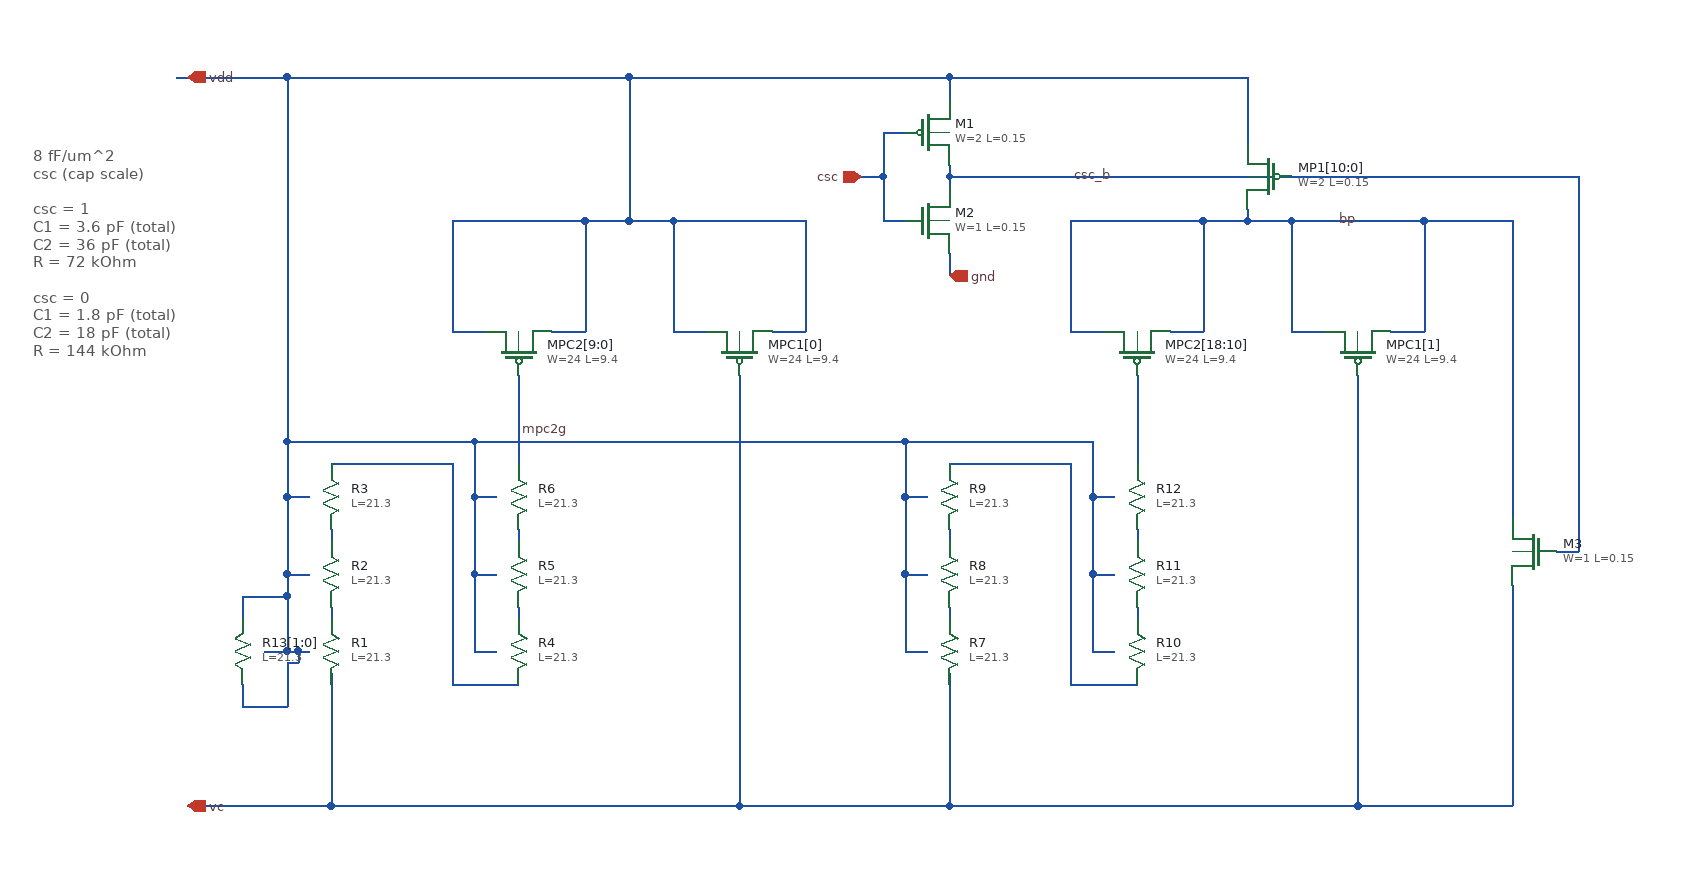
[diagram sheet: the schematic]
v {xschem version=3.4.5 file_version=1.2
}
G {}
K {}
V {}
S {}
E {}
T {8 fF/um^2
csc (cap scale)

csc = 1
C1 = 3.6 pF (total)
C2 = 36 pF (total)
R = 72 kOhm 

csc = 0
C1 = 1.8 pF (total)
C2 = 18 pF (total)
R = 144 kOhm } -50 -720 0 0 0.4 0.4 {}
N 190 -260 200 -260 {
lab=vdd}
N 530 -650 650 -650 {
lab=vdd}
N 330 -550 360 -550 {
lab=vdd}
N 330 -650 330 -550 {
lab=vdd}
N 420 -550 450 -550 {
lab=vdd}
N 450 -650 450 -550 {
lab=vdd}
N 330 -650 450 -650 {
lab=vdd}
N 220 -430 330 -430 {
lab=#net1}
N 390 -510 390 -430 {
lab=mpc2g}
N 530 -550 560 -550 {
lab=vdd}
N 530 -650 530 -550 {
lab=vdd}
N 620 -550 650 -550 {
lab=vdd}
N 650 -650 650 -550 {
lab=vdd}
N 590 -510 590 -120 {
lab=vc}
N 1150 -120 1290 -120 {
lab=vc}
N 490 -650 530 -650 {
lab=vdd}
N 220 -240 220 -120 {
lab=vc}
N 1090 -650 1210 -650 {
lab=csc_b}
N 890 -550 920 -550 {
lab=csc_b}
N 890 -650 890 -550 {
lab=csc_b}
N 980 -550 1010 -550 {
lab=csc_b}
N 1010 -650 1010 -550 {
lab=csc_b}
N 890 -650 1010 -650 {
lab=csc_b}
N 1090 -550 1120 -550 {
lab=csc_b}
N 1090 -650 1090 -550 {
lab=csc_b}
N 1180 -550 1210 -550 {
lab=csc_b}
N 1210 -650 1210 -550 {
lab=csc_b}
N 1150 -510 1150 -120 {
lab=vc}
N 1050 -650 1090 -650 {
lab=csc_b}
N 780 -690 780 -680 {
lab=csc_b}
N 720 -730 740 -730 {
lab=csc}
N 720 -690 720 -650 {
lab=csc}
N 720 -650 740 -650 {
lab=csc}
N 780 -780 780 -760 {
lab=vdd}
N 780 -620 780 -600 {
lab=gnd}
N 1010 -650 1050 -650 {
lab=csc_b}
N 1210 -650 1290 -650 {
lab=csc_b}
N 1290 -650 1290 -380 {
lab=csc_b}
N 1290 -320 1290 -120 {
lab=vc}
N 180 -400 180 -330 {
lab=vdd}
N 780 -780 1050 -780 {
lab=vdd}
N 80 -780 180 -780 {
lab=vdd}
N 1330 -350 1350 -350 {
lab=csc_b}
N 490 -780 780 -780 {
lab=vdd}
N 490 -780 490 -650 {
lab=vdd}
N 180 -780 490 -780 {
lab=vdd}
N 450 -650 490 -650 {
lab=vdd}
N 1050 -660 1050 -650 {
lab=csc_b}
N 1350 -690 1350 -350 {
lab=csc_b}
N 1050 -780 1050 -720 {
lab=vdd}
N 780 -690 1350 -690 {
lab=csc_b}
N 780 -700 780 -690 {
lab=csc_b}
N 700 -690 720 -690 {
lab=csc}
N 720 -730 720 -690 {
lab=csc}
N 180 -310 180 -260 {
lab=vdd}
N 220 -370 220 -360 {
lab=#net2}
N 220 -300 220 -290 {
lab=#net3}
N 180 -330 200 -330 {
lab=vdd}
N 180 -400 200 -400 {
lab=vdd}
N 180 -450 180 -400 {
lab=vdd}
N 350 -260 370 -260 {
lab=vdd}
N 350 -330 350 -260 {
lab=vdd}
N 390 -370 390 -360 {
lab=#net4}
N 390 -300 390 -290 {
lab=#net5}
N 350 -330 370 -330 {
lab=vdd}
N 350 -400 370 -400 {
lab=vdd}
N 180 -780 180 -450 {
lab=vdd}
N 330 -230 390 -230 {
lab=#net1}
N 330 -430 330 -230 {
lab=#net1}
N 350 -400 350 -330 {
lab=vdd}
N 350 -450 350 -400 {
lab=vdd}
N 740 -260 760 -260 {
lab=#net6}
N 780 -430 890 -430 {
lab=#net7}
N 950 -510 950 -430 {
lab=#net8}
N 780 -240 780 -120 {
lab=vc}
N 740 -400 740 -330 {
lab=#net6}
N 740 -330 740 -260 {
lab=#net6}
N 780 -370 780 -360 {
lab=#net9}
N 780 -300 780 -290 {
lab=#net10}
N 740 -330 760 -330 {
lab=#net6}
N 740 -400 760 -400 {
lab=#net6}
N 740 -450 740 -400 {
lab=#net6}
N 910 -260 930 -260 {
lab=#net6}
N 910 -330 910 -260 {
lab=#net6}
N 950 -370 950 -360 {
lab=#net11}
N 950 -300 950 -290 {
lab=#net12}
N 910 -330 930 -330 {
lab=#net6}
N 910 -400 930 -400 {
lab=#net6}
N 740 -450 910 -450 {
lab=#net6}
N 890 -230 950 -230 {
lab=#net7}
N 890 -430 890 -230 {
lab=#net7}
N 910 -400 910 -330 {
lab=#net6}
N 910 -450 910 -400 {
lab=#net6}
N 220 -120 590 -120 {
lab=vc}
N 90 -120 220 -120 {
lab=vc}
N 780 -120 1150 -120 {
lab=vc}
N 590 -120 780 -120 {
lab=vc}
N 160 -260 180 -260 {
lab=vdd}
N 140 -310 140 -290 {
lab=vdd}
N 140 -310 180 -310 {
lab=vdd}
N 180 -330 180 -310 {
lab=vdd}
N 140 -230 140 -210 {
lab=vdd}
N 140 -210 180 -210 {
lab=vdd}
N 180 -250 180 -210 {
lab=vdd}
N 180 -250 190 -250 {
lab=vdd}
N 190 -260 190 -250 {
lab=vdd}
N 180 -260 190 -260 {
lab=vdd}
N 350 -450 740 -450 {}
N 180 -450 350 -450 {
lab=vdd}
C {title_nologo.sym} 200 0 0 0 {name=l1 author="ejfogleman"}
C {iopin.sym} 90 -120 0 1 {name=p1 lab=vc}
C {iopin.sym} 90 -780 0 1 {name=p2 lab=vdd}
C {sky130_fd_pr/pfet3_01v8_lvt.sym} 390 -530 3 0 {name=MPC2[9:0]
W=24
L=9.4
body=vdd
nf=4
mult=1
ad="'int((nf+1)/2) * W/nf * 0.29'" 
pd="'2*int((nf+1)/2) * (W/nf + 0.29)'"
as="'int((nf+2)/2) * W/nf * 0.29'" 
ps="'2*int((nf+2)/2) * (W/nf + 0.29)'"
nrd="'0.29 / W'" nrs="'0.29 / W'"
sa=0 sb=0 sd=0
model=pfet_01v8_lvt
spiceprefix=X
}
C {sky130_fd_pr/pfet3_01v8_lvt.sym} 590 -530 3 0 {name=MPC1[0]
W=24
L=9.4	
body=vdd
nf=4
mult=1
ad="'int((nf+1)/2) * W/nf * 0.29'" 
pd="'2*int((nf+1)/2) * (W/nf + 0.29)'"
as="'int((nf+2)/2) * W/nf * 0.29'" 
ps="'2*int((nf+2)/2) * (W/nf + 0.29)'"
nrd="'0.29 / W'" nrs="'0.29 / W'"
sa=0 sb=0 sd=0
model=pfet_01v8_lvt
spiceprefix=X
}
C {lab_wire.sym} 390 -460 0 1 {name=p3 sig_type=std_logic lab=mpc2g}
C {sky130_fd_pr/pfet3_01v8_lvt.sym} 950 -530 3 0 {name=MPC2[18:10]
W=24
L=9.4
body=vdd
nf=4
mult=1
ad="'int((nf+1)/2) * W/nf * 0.29'" 
pd="'2*int((nf+1)/2) * (W/nf + 0.29)'"
as="'int((nf+2)/2) * W/nf * 0.29'" 
ps="'2*int((nf+2)/2) * (W/nf + 0.29)'"
nrd="'0.29 / W'" nrs="'0.29 / W'"
sa=0 sb=0 sd=0
model=pfet_01v8_lvt
spiceprefix=X
}
C {sky130_fd_pr/pfet3_01v8_lvt.sym} 1150 -530 3 0 {name=MPC1[1]
W=24
L=9.4	
body=vdd
nf=4
mult=1
ad="'int((nf+1)/2) * W/nf * 0.29'" 
pd="'2*int((nf+1)/2) * (W/nf + 0.29)'"
as="'int((nf+2)/2) * W/nf * 0.29'" 
ps="'2*int((nf+2)/2) * (W/nf + 0.29)'"
nrd="'0.29 / W'" nrs="'0.29 / W'"
sa=0 sb=0 sd=0
model=pfet_01v8_lvt
spiceprefix=X
}
C {sky130_fd_pr/pfet3_01v8_hvt.sym} 760 -730 0 0 {name=M1
W=2
L=0.15
body=vdd
nf=1
mult=1
ad="'int((nf+1)/2) * W/nf * 0.29'" 
pd="'2*int((nf+1)/2) * (W/nf + 0.29)'"
as="'int((nf+2)/2) * W/nf * 0.29'" 
ps="'2*int((nf+2)/2) * (W/nf + 0.29)'"
nrd="'0.29 / W'" nrs="'0.29 / W'"
sa=0 sb=0 sd=0
model=pfet_01v8_hvt
spiceprefix=X
}
C {sky130_fd_pr/nfet3_01v8.sym} 760 -650 0 0 {name=M2
W=1
L=0.15
body=gnd
nf=1
mult=1
ad="'int((nf+1)/2) * W/nf * 0.29'" 
pd="'2*int((nf+1)/2) * (W/nf + 0.29)'"
as="'int((nf+2)/2) * W/nf * 0.29'" 
ps="'2*int((nf+2)/2) * (W/nf + 0.29)'"
nrd="'0.29 / W'" nrs="'0.29 / W'"
sa=0 sb=0 sd=0
model=nfet_01v8
spiceprefix=X
}
C {iopin.sym} 780 -600 0 1 {name=p7 lab=gnd}
C {sky130_fd_pr/pfet3_01v8_hvt.sym} 1070 -690 0 1 {name=MP1[10:0]
W=2
L=0.15
body=vdd
nf=1
mult=1
ad="'int((nf+1)/2) * W/nf * 0.29'" 
pd="'2*int((nf+1)/2) * (W/nf + 0.29)'"
as="'int((nf+2)/2) * W/nf * 0.29'" 
ps="'2*int((nf+2)/2) * (W/nf + 0.29)'"
nrd="'0.29 / W'" nrs="'0.29 / W'"
sa=0 sb=0 sd=0
model=pfet_01v8_hvt
spiceprefix=X
}
C {sky130_fd_pr/nfet3_01v8.sym} 1310 -350 0 1 {name=M3
W=1
L=0.15
body=gnd
nf=1
mult=1
ad="'int((nf+1)/2) * W/nf * 0.29'" 
pd="'2*int((nf+1)/2) * (W/nf + 0.29)'"
as="'int((nf+2)/2) * W/nf * 0.29'" 
ps="'2*int((nf+2)/2) * (W/nf + 0.29)'"
nrd="'0.29 / W'" nrs="'0.29 / W'"
sa=0 sb=0 sd=0
model=nfet_01v8
spiceprefix=X
}
C {ipin.sym} 700 -690 0 0 {name=p5 lab=csc}
C {sky130_fd_pr/res_high_po_0p35.sym} 220 -260 0 0 {name=R1
L=21.3
model=res_high_po_0p35
spiceprefix=X
mult=1}
C {sky130_fd_pr/res_high_po_0p35.sym} 220 -330 0 0 {name=R2
L=21.3
model=res_high_po_0p35
spiceprefix=X
mult=1}
C {sky130_fd_pr/res_high_po_0p35.sym} 220 -400 0 0 {name=R3
L=21.3
model=res_high_po_0p35
spiceprefix=X
mult=1}
C {sky130_fd_pr/res_high_po_0p35.sym} 390 -260 0 0 {name=R4
L=21.3
model=res_high_po_0p35
spiceprefix=X
mult=1}
C {sky130_fd_pr/res_high_po_0p35.sym} 390 -330 0 0 {name=R5
L=21.3
model=res_high_po_0p35
spiceprefix=X
mult=1}
C {sky130_fd_pr/res_high_po_0p35.sym} 390 -400 0 0 {name=R6
L=21.3
model=res_high_po_0p35
spiceprefix=X
mult=1}
C {sky130_fd_pr/res_high_po_0p35.sym} 780 -260 0 0 {name=R7
L=21.3
model=res_high_po_0p35
spiceprefix=X
mult=1}
C {sky130_fd_pr/res_high_po_0p35.sym} 780 -330 0 0 {name=R8
L=21.3
model=res_high_po_0p35
spiceprefix=X
mult=1}
C {sky130_fd_pr/res_high_po_0p35.sym} 780 -400 0 0 {name=R9
L=21.3
model=res_high_po_0p35
spiceprefix=X
mult=1}
C {sky130_fd_pr/res_high_po_0p35.sym} 950 -260 0 0 {name=R10
L=21.3
model=res_high_po_0p35
spiceprefix=X
mult=1}
C {sky130_fd_pr/res_high_po_0p35.sym} 950 -330 0 0 {name=R11
L=21.3
model=res_high_po_0p35
spiceprefix=X
mult=1}
C {sky130_fd_pr/res_high_po_0p35.sym} 950 -400 0 0 {name=R12
L=21.3
model=res_high_po_0p35
spiceprefix=X
mult=1}
C {sky130_fd_pr/res_high_po_0p35.sym} 140 -260 0 1 {name=R13[1:0]
L=21.3
model=res_high_po_0p35
spiceprefix=X
mult=1}
C {lab_wire.sym} 890 -690 0 1 {name=p4 sig_type=std_logic lab=csc_b}
C {lab_wire.sym} 1130 -650 0 1 {name=p6 sig_type=std_logic lab=bp}
